VERSION 5.7 ;
BUSBITCHARS "[]" ;
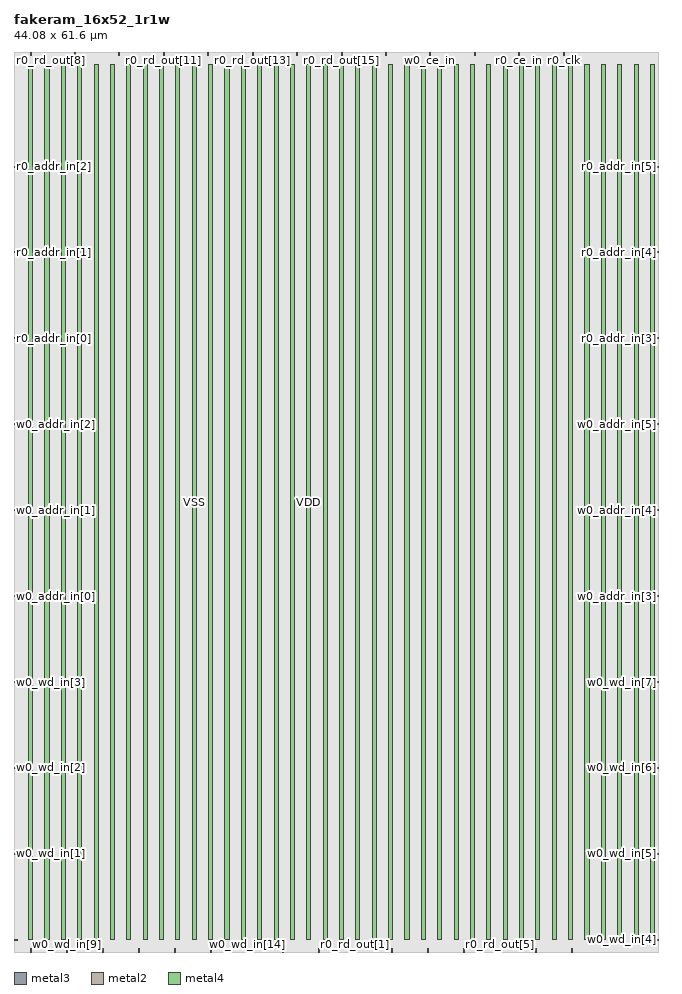
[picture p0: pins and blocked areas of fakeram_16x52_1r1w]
MACRO fakeram_16x52_1r1w
  FOREIGN fakeram_16x52_1r1w 0 0 ;
  SYMMETRY X Y R90 ;
  SIZE 44.080 BY 61.600 ;
  CLASS BLOCK ;
  PIN w0_wd_in[0]
    DIRECTION INPUT ;
    USE SIGNAL ;
    SHAPE ABUTMENT ;
    PORT
      LAYER metal3 ;
      RECT 0.000 0.805 0.210 0.875 ;
    END
  END w0_wd_in[0]
  PIN w0_wd_in[1]
    DIRECTION INPUT ;
    USE SIGNAL ;
    SHAPE ABUTMENT ;
    PORT
      LAYER metal3 ;
      RECT 0.000 6.685 0.210 6.755 ;
    END
  END w0_wd_in[1]
  PIN w0_wd_in[2]
    DIRECTION INPUT ;
    USE SIGNAL ;
    SHAPE ABUTMENT ;
    PORT
      LAYER metal3 ;
      RECT 0.000 12.565 0.210 12.635 ;
    END
  END w0_wd_in[2]
  PIN w0_wd_in[3]
    DIRECTION INPUT ;
    USE SIGNAL ;
    SHAPE ABUTMENT ;
    PORT
      LAYER metal3 ;
      RECT 0.000 18.445 0.210 18.515 ;
    END
  END w0_wd_in[3]
  PIN w0_wd_in[4]
    DIRECTION INPUT ;
    USE SIGNAL ;
    SHAPE ABUTMENT ;
    PORT
      LAYER metal3 ;
      RECT 43.870 0.805 44.080 0.875 ;
    END
  END w0_wd_in[4]
  PIN w0_wd_in[5]
    DIRECTION INPUT ;
    USE SIGNAL ;
    SHAPE ABUTMENT ;
    PORT
      LAYER metal3 ;
      RECT 43.870 6.685 44.080 6.755 ;
    END
  END w0_wd_in[5]
  PIN w0_wd_in[6]
    DIRECTION INPUT ;
    USE SIGNAL ;
    SHAPE ABUTMENT ;
    PORT
      LAYER metal3 ;
      RECT 43.870 12.565 44.080 12.635 ;
    END
  END w0_wd_in[6]
  PIN w0_wd_in[7]
    DIRECTION INPUT ;
    USE SIGNAL ;
    SHAPE ABUTMENT ;
    PORT
      LAYER metal3 ;
      RECT 43.870 18.445 44.080 18.515 ;
    END
  END w0_wd_in[7]
  PIN w0_wd_in[8]
    DIRECTION INPUT ;
    USE SIGNAL ;
    SHAPE ABUTMENT ;
    PORT
      LAYER metal2 ;
      RECT 1.105 0.000 1.175 0.210 ;
    END
  END w0_wd_in[8]
  PIN w0_wd_in[9]
    DIRECTION INPUT ;
    USE SIGNAL ;
    SHAPE ABUTMENT ;
    PORT
      LAYER metal2 ;
      RECT 3.575 0.000 3.645 0.210 ;
    END
  END w0_wd_in[9]
  PIN w0_wd_in[10]
    DIRECTION INPUT ;
    USE SIGNAL ;
    SHAPE ABUTMENT ;
    PORT
      LAYER metal2 ;
      RECT 6.045 0.000 6.115 0.210 ;
    END
  END w0_wd_in[10]
  PIN w0_wd_in[11]
    DIRECTION INPUT ;
    USE SIGNAL ;
    SHAPE ABUTMENT ;
    PORT
      LAYER metal2 ;
      RECT 8.515 0.000 8.585 0.210 ;
    END
  END w0_wd_in[11]
  PIN w0_wd_in[12]
    DIRECTION INPUT ;
    USE SIGNAL ;
    SHAPE ABUTMENT ;
    PORT
      LAYER metal2 ;
      RECT 10.985 0.000 11.055 0.210 ;
    END
  END w0_wd_in[12]
  PIN w0_wd_in[13]
    DIRECTION INPUT ;
    USE SIGNAL ;
    SHAPE ABUTMENT ;
    PORT
      LAYER metal2 ;
      RECT 13.455 0.000 13.525 0.210 ;
    END
  END w0_wd_in[13]
  PIN w0_wd_in[14]
    DIRECTION INPUT ;
    USE SIGNAL ;
    SHAPE ABUTMENT ;
    PORT
      LAYER metal2 ;
      RECT 15.925 0.000 15.995 0.210 ;
    END
  END w0_wd_in[14]
  PIN w0_wd_in[15]
    DIRECTION INPUT ;
    USE SIGNAL ;
    SHAPE ABUTMENT ;
    PORT
      LAYER metal2 ;
      RECT 18.395 0.000 18.465 0.210 ;
    END
  END w0_wd_in[15]
  PIN r0_rd_out[0]
    DIRECTION OUTPUT ;
    USE SIGNAL ;
    SHAPE ABUTMENT ;
    PORT
      LAYER metal2 ;
      RECT 20.865 0.000 20.935 0.210 ;
    END
  END r0_rd_out[0]
  PIN r0_rd_out[1]
    DIRECTION OUTPUT ;
    USE SIGNAL ;
    SHAPE ABUTMENT ;
    PORT
      LAYER metal2 ;
      RECT 23.335 0.000 23.405 0.210 ;
    END
  END r0_rd_out[1]
  PIN r0_rd_out[2]
    DIRECTION OUTPUT ;
    USE SIGNAL ;
    SHAPE ABUTMENT ;
    PORT
      LAYER metal2 ;
      RECT 25.805 0.000 25.875 0.210 ;
    END
  END r0_rd_out[2]
  PIN r0_rd_out[3]
    DIRECTION OUTPUT ;
    USE SIGNAL ;
    SHAPE ABUTMENT ;
    PORT
      LAYER metal2 ;
      RECT 28.275 0.000 28.345 0.210 ;
    END
  END r0_rd_out[3]
  PIN r0_rd_out[4]
    DIRECTION OUTPUT ;
    USE SIGNAL ;
    SHAPE ABUTMENT ;
    PORT
      LAYER metal2 ;
      RECT 30.745 0.000 30.815 0.210 ;
    END
  END r0_rd_out[4]
  PIN r0_rd_out[5]
    DIRECTION OUTPUT ;
    USE SIGNAL ;
    SHAPE ABUTMENT ;
    PORT
      LAYER metal2 ;
      RECT 33.215 0.000 33.285 0.210 ;
    END
  END r0_rd_out[5]
  PIN r0_rd_out[6]
    DIRECTION OUTPUT ;
    USE SIGNAL ;
    SHAPE ABUTMENT ;
    PORT
      LAYER metal2 ;
      RECT 35.685 0.000 35.755 0.210 ;
    END
  END r0_rd_out[6]
  PIN r0_rd_out[7]
    DIRECTION OUTPUT ;
    USE SIGNAL ;
    SHAPE ABUTMENT ;
    PORT
      LAYER metal2 ;
      RECT 38.155 0.000 38.225 0.210 ;
    END
  END r0_rd_out[7]
  PIN r0_rd_out[8]
    DIRECTION OUTPUT ;
    USE SIGNAL ;
    SHAPE ABUTMENT ;
    PORT
      LAYER metal2 ;
      RECT 1.105 61.390 1.175 61.600 ;
    END
  END r0_rd_out[8]
  PIN r0_rd_out[9]
    DIRECTION OUTPUT ;
    USE SIGNAL ;
    SHAPE ABUTMENT ;
    PORT
      LAYER metal2 ;
      RECT 4.145 61.390 4.215 61.600 ;
    END
  END r0_rd_out[9]
  PIN r0_rd_out[10]
    DIRECTION OUTPUT ;
    USE SIGNAL ;
    SHAPE ABUTMENT ;
    PORT
      LAYER metal2 ;
      RECT 7.185 61.390 7.255 61.600 ;
    END
  END r0_rd_out[10]
  PIN r0_rd_out[11]
    DIRECTION OUTPUT ;
    USE SIGNAL ;
    SHAPE ABUTMENT ;
    PORT
      LAYER metal2 ;
      RECT 10.225 61.390 10.295 61.600 ;
    END
  END r0_rd_out[11]
  PIN r0_rd_out[12]
    DIRECTION OUTPUT ;
    USE SIGNAL ;
    SHAPE ABUTMENT ;
    PORT
      LAYER metal2 ;
      RECT 13.265 61.390 13.335 61.600 ;
    END
  END r0_rd_out[12]
  PIN r0_rd_out[13]
    DIRECTION OUTPUT ;
    USE SIGNAL ;
    SHAPE ABUTMENT ;
    PORT
      LAYER metal2 ;
      RECT 16.305 61.390 16.375 61.600 ;
    END
  END r0_rd_out[13]
  PIN r0_rd_out[14]
    DIRECTION OUTPUT ;
    USE SIGNAL ;
    SHAPE ABUTMENT ;
    PORT
      LAYER metal2 ;
      RECT 19.345 61.390 19.415 61.600 ;
    END
  END r0_rd_out[14]
  PIN r0_rd_out[15]
    DIRECTION OUTPUT ;
    USE SIGNAL ;
    SHAPE ABUTMENT ;
    PORT
      LAYER metal2 ;
      RECT 22.385 61.390 22.455 61.600 ;
    END
  END r0_rd_out[15]
  PIN w0_addr_in[0]
    DIRECTION INPUT ;
    USE SIGNAL ;
    SHAPE ABUTMENT ;
    PORT
      LAYER metal3 ;
      RECT 0.000 24.325 0.210 24.395 ;
    END
  END w0_addr_in[0]
  PIN w0_addr_in[1]
    DIRECTION INPUT ;
    USE SIGNAL ;
    SHAPE ABUTMENT ;
    PORT
      LAYER metal3 ;
      RECT 0.000 30.205 0.210 30.275 ;
    END
  END w0_addr_in[1]
  PIN w0_addr_in[2]
    DIRECTION INPUT ;
    USE SIGNAL ;
    SHAPE ABUTMENT ;
    PORT
      LAYER metal3 ;
      RECT 0.000 36.085 0.210 36.155 ;
    END
  END w0_addr_in[2]
  PIN w0_addr_in[3]
    DIRECTION INPUT ;
    USE SIGNAL ;
    SHAPE ABUTMENT ;
    PORT
      LAYER metal3 ;
      RECT 43.870 24.325 44.080 24.395 ;
    END
  END w0_addr_in[3]
  PIN w0_addr_in[4]
    DIRECTION INPUT ;
    USE SIGNAL ;
    SHAPE ABUTMENT ;
    PORT
      LAYER metal3 ;
      RECT 43.870 30.205 44.080 30.275 ;
    END
  END w0_addr_in[4]
  PIN w0_addr_in[5]
    DIRECTION INPUT ;
    USE SIGNAL ;
    SHAPE ABUTMENT ;
    PORT
      LAYER metal3 ;
      RECT 43.870 36.085 44.080 36.155 ;
    END
  END w0_addr_in[5]
  PIN r0_addr_in[0]
    DIRECTION INPUT ;
    USE SIGNAL ;
    SHAPE ABUTMENT ;
    PORT
      LAYER metal3 ;
      RECT 0.000 41.965 0.210 42.035 ;
    END
  END r0_addr_in[0]
  PIN r0_addr_in[1]
    DIRECTION INPUT ;
    USE SIGNAL ;
    SHAPE ABUTMENT ;
    PORT
      LAYER metal3 ;
      RECT 0.000 47.845 0.210 47.915 ;
    END
  END r0_addr_in[1]
  PIN r0_addr_in[2]
    DIRECTION INPUT ;
    USE SIGNAL ;
    SHAPE ABUTMENT ;
    PORT
      LAYER metal3 ;
      RECT 0.000 53.725 0.210 53.795 ;
    END
  END r0_addr_in[2]
  PIN r0_addr_in[3]
    DIRECTION INPUT ;
    USE SIGNAL ;
    SHAPE ABUTMENT ;
    PORT
      LAYER metal3 ;
      RECT 43.870 41.965 44.080 42.035 ;
    END
  END r0_addr_in[3]
  PIN r0_addr_in[4]
    DIRECTION INPUT ;
    USE SIGNAL ;
    SHAPE ABUTMENT ;
    PORT
      LAYER metal3 ;
      RECT 43.870 47.845 44.080 47.915 ;
    END
  END r0_addr_in[4]
  PIN r0_addr_in[5]
    DIRECTION INPUT ;
    USE SIGNAL ;
    SHAPE ABUTMENT ;
    PORT
      LAYER metal3 ;
      RECT 43.870 53.725 44.080 53.795 ;
    END
  END r0_addr_in[5]
  PIN w0_we_in
    DIRECTION INPUT ;
    USE SIGNAL ;
    SHAPE ABUTMENT ;
    PORT
      LAYER metal2 ;
      RECT 25.425 61.390 25.495 61.600 ;
    END
  END w0_we_in
  PIN w0_ce_in
    DIRECTION INPUT ;
    USE SIGNAL ;
    SHAPE ABUTMENT ;
    PORT
      LAYER metal2 ;
      RECT 28.465 61.390 28.535 61.600 ;
    END
  END w0_ce_in
  PIN w0_clk
    DIRECTION INPUT ;
    USE SIGNAL ;
    SHAPE ABUTMENT ;
    PORT
      LAYER metal2 ;
      RECT 31.505 61.390 31.575 61.600 ;
    END
  END w0_clk
  PIN r0_ce_in
    DIRECTION INPUT ;
    USE SIGNAL ;
    SHAPE ABUTMENT ;
    PORT
      LAYER metal2 ;
      RECT 34.545 61.390 34.615 61.600 ;
    END
  END r0_ce_in
  PIN r0_clk
    DIRECTION INPUT ;
    USE SIGNAL ;
    SHAPE ABUTMENT ;
    PORT
      LAYER metal2 ;
      RECT 37.585 61.390 37.655 61.600 ;
    END
  END r0_clk
  PIN VSS
    DIRECTION INOUT ;
    USE GROUND ;
    PORT
      LAYER metal4 ;
      RECT 1.000 0.840 1.280 60.760 ;
      RECT 3.240 0.840 3.520 60.760 ;
      RECT 5.480 0.840 5.760 60.760 ;
      RECT 7.720 0.840 8.000 60.760 ;
      RECT 9.960 0.840 10.240 60.760 ;
      RECT 12.200 0.840 12.480 60.760 ;
      RECT 14.440 0.840 14.720 60.760 ;
      RECT 16.680 0.840 16.960 60.760 ;
      RECT 18.920 0.840 19.200 60.760 ;
      RECT 21.160 0.840 21.440 60.760 ;
      RECT 23.400 0.840 23.680 60.760 ;
      RECT 25.640 0.840 25.920 60.760 ;
      RECT 27.880 0.840 28.160 60.760 ;
      RECT 30.120 0.840 30.400 60.760 ;
      RECT 32.360 0.840 32.640 60.760 ;
      RECT 34.600 0.840 34.880 60.760 ;
      RECT 36.840 0.840 37.120 60.760 ;
      RECT 39.080 0.840 39.360 60.760 ;
      RECT 41.320 0.840 41.600 60.760 ;
      RECT 43.560 0.840 43.840 60.760 ;
    END
  END VSS
  PIN VDD
    DIRECTION INOUT ;
    USE POWER ;
    PORT
      LAYER metal4 ;
      RECT 2.120 0.840 2.400 60.760 ;
      RECT 4.360 0.840 4.640 60.760 ;
      RECT 6.600 0.840 6.880 60.760 ;
      RECT 8.840 0.840 9.120 60.760 ;
      RECT 11.080 0.840 11.360 60.760 ;
      RECT 13.320 0.840 13.600 60.760 ;
      RECT 15.560 0.840 15.840 60.760 ;
      RECT 17.800 0.840 18.080 60.760 ;
      RECT 20.040 0.840 20.320 60.760 ;
      RECT 22.280 0.840 22.560 60.760 ;
      RECT 24.520 0.840 24.800 60.760 ;
      RECT 26.760 0.840 27.040 60.760 ;
      RECT 29.000 0.840 29.280 60.760 ;
      RECT 31.240 0.840 31.520 60.760 ;
      RECT 33.480 0.840 33.760 60.760 ;
      RECT 35.720 0.840 36.000 60.760 ;
      RECT 37.960 0.840 38.240 60.760 ;
      RECT 40.200 0.840 40.480 60.760 ;
      RECT 42.440 0.840 42.720 60.760 ;
    END
  END VDD
  OBS
    LAYER metal1 ;
    RECT 0 0 44.080 61.600 ;
    LAYER metal2 ;
    RECT 0 0 44.080 61.600 ;
    LAYER metal3 ;
    RECT 0 0 44.080 61.600 ;
    LAYER metal4 ;
    RECT 0 0 44.080 61.600 ;
    LAYER OVERLAP ;
    RECT 0 0 44.080 61.600 ;
  END
END fakeram_16x52_1r1w

END LIBRARY
